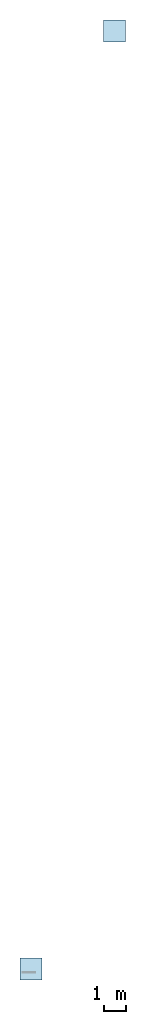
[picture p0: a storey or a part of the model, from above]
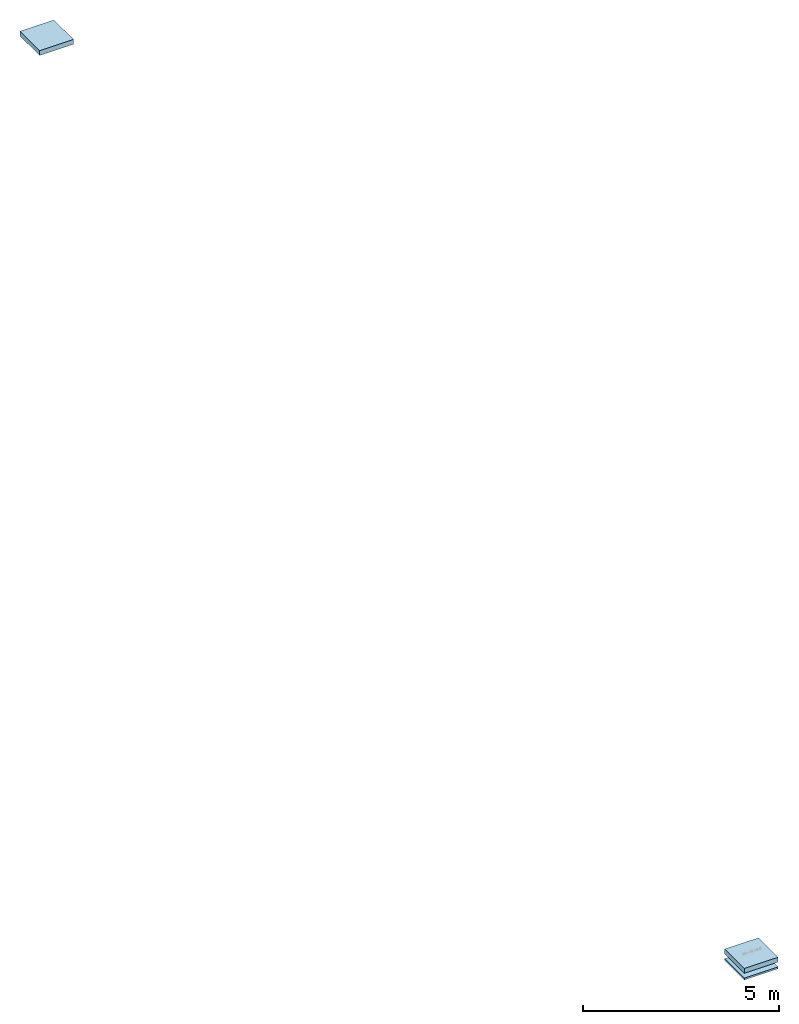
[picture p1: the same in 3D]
Properties of the parts of a building model (IFC4)

# File
Description: ViewDefinition [ReferenceView_V1.2], RevitIdentifiers [VersionGUID: 25224f80-5d8e-4640-b9d8-b88f8e84a847, NumberOfSaves: 3], CoordinateReference [CoordinateBase: Gemeinsam genutzte Koordinaten], ExchangeRequirement [Architecture]
File name: 2018_01
Time: 2023-07-05T11:44:28+01:00
Written by: ODA SDAI 23.12
Made in: Autodesk Revit 24.0.5.432 (DEU) - IFC 24.0.5.432

# IfcProject, 2018_01
Phase: Projekt Status

# IfcSite, Default
RefLatitude: 48, 8, 15, 359802; RefLongitude: 11, 34, 47, 783432; RefElevation: 0 m
Pset_SiteCommon - Reference: Projektinformationen

# IfcBuildingElementProxy: Modelltext:075mm Arial, Modelltext:075mm Arial:2510550
In: Default
Type - Pset_BuildingElementProxyCommon - IsExternal: no
Pset_BuildingElementProxyCommon - Reference: 075mm Arial
Pset_EnvironmentalImpactIndicators - Reference: 075mm Arial
Qto_BuildingElementProxyQuantities - NetSurfaceArea: 0.0977671 m2; NetVolume: 0.000317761 m3

# IfcElementAssembly: Dächer Baugruppe:fbimSg_Roof_bc_WOD_vis_at_NTR_natuREbuilt_SD-HS-HLÜ_GK3_55cm, Dächer Baugruppe:fbimSg_Roof_bc_WOD_vis_at_NTR_natuREbuilt_SD-HS-HLÜ_GK3_55cm:2510578
In: Default
PredefinedType: USERDEFINED
Pset_ElementAssemblyCommon - Reference: fbimSg_Roof_bc_WOD_vis_at_NTR_natuREbuilt_SD-HS-HLÜ_GK3_55cm; sets with these values: 2

# IfcRoof: Basisdach:fbimSg_Roof_dp_DRW_vis_at_NTR_natuREbuilt_SD-HS-HLÜ_GK3_u_6cm, Basisdach:fbimSg_Roof_dp_DRW_vis_at_NTR_natuREbuilt_SD-HS-HLÜ_GK3_u_6cm:2510571
In: Default
Type - Pset_RoofCommon - IsExternal: yes
Material: fbim_12401520_AT_OSB, OENORM A6240 Dämmstoff (Weich), fbim_16101505_AT_Gipsfaserplatte
Pset_EnvironmentalImpactIndicators - Reference: fbimSg_Roof_dp_DRW_vis_at_NTR_natuREbuilt_SD-HS-HLÜ_GK3_u_6cm
Pset_RoofCommon - Reference: fbimSg_Roof_dp_DRW_vis_at_NTR_natuREbuilt_SD-HS-HLÜ_GK3_u_6cm
Qto_RoofBaseQuantities - GrossArea: 1 m2; ProjectedArea: 1 m2

# IfcRoof: Basisdach:fbimSg_Roof_dp_INH_vis_at_NTR_natuREbuilt_SD-HS-HLÜ_GK3_o_14, Basisdach:fbimSg_Roof_dp_INH_vis_at_NTR_natuREbuilt_SD-HS-HLÜ_GK3_o_14:2510562
In: Default
Type - Pset_RoofCommon - IsExternal: yes
Material: fbim_12451505_AT_001_Tondachstein, fbim_12400520_AT_001_Vollholz_Lattung_Fichte (2), fbim_14100530_AT_Holzfaserdaemmung, OENORM A6240 Dämmstoff (Weich)
Pset_EnvironmentalImpactIndicators - Reference: fbimSg_Roof_dp_INH_vis_at_NTR_natuREbuilt_SD-HS-HLÜ_GK3_o_14
Pset_RoofCommon - Reference: fbimSg_Roof_dp_INH_vis_at_NTR_natuREbuilt_SD-HS-HLÜ_GK3_o_14
Qto_RoofBaseQuantities - GrossArea: 1 m2; ProjectedArea: 1 m2

# IfcRoof: Basisdach:fbimSg_Roof_sb_WOD_vis_at_NTR_natuREbuilt_SD-HS-HLÜ_GK3_k_26cm, Basisdach:fbimSg_Roof_sb_WOD_vis_at_NTR_natuREbuilt_SD-HS-HLÜ_GK3_k_26cm:2510553
In: Default
Pset_EnvironmentalImpactIndicators - Reference: fbimSg_Roof_sb_WOD_vis_at_NTR_natuREbuilt_SD-HS-HLÜ_GK3_k_26cm
Pset_RoofCommon - Reference: fbimSg_Roof_sb_WOD_vis_at_NTR_natuREbuilt_SD-HS-HLÜ_GK3_k_26cm; IsExternal: yes
Qto_RoofBaseQuantities - ProjectedArea: 1 m2

# IfcSlab: Basisdach:fbimSg_Roof_sb_WOD_vis_at_NTR_natuREbuilt_SD-HS-HLÜ_GK3_k_26cm, Basisdach:fbimSg_Roof_sb_WOD_vis_at_NTR_natuREbuilt_SD-HS-HLÜ_GK3_k_26cm:2510553
In: Default
Type - PredefinedType: ROOF
Type - Pset_SlabCommon - IsExternal: yes
Material: fbim_12400520_AT_Konstruktionsvollholz_Fichte
Pset_EnvironmentalImpactIndicators - Reference: fbimSg_Roof_sb_WOD_vis_at_NTR_natuREbuilt_SD-HS-HLÜ_GK3_k_26cm; sets with these values: 2
Pset_SlabCommon - Reference: fbimSg_Roof_sb_WOD_vis_at_NTR_natuREbuilt_SD-HS-HLÜ_GK3_k_26cm; PitchAngle: 0 deg
Qto_SlabBaseQuantities - Length: 0.15 m; Perimeter: 4 m; GrossArea: 0.092903 m2; GrossVolume: 0.0139355 m3; NetVolume: 0.15 m3
